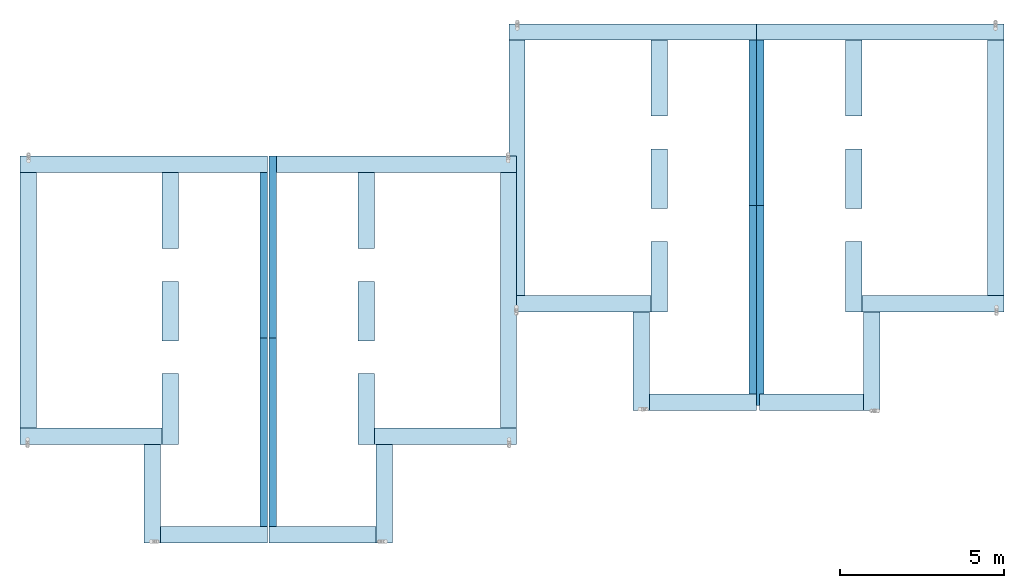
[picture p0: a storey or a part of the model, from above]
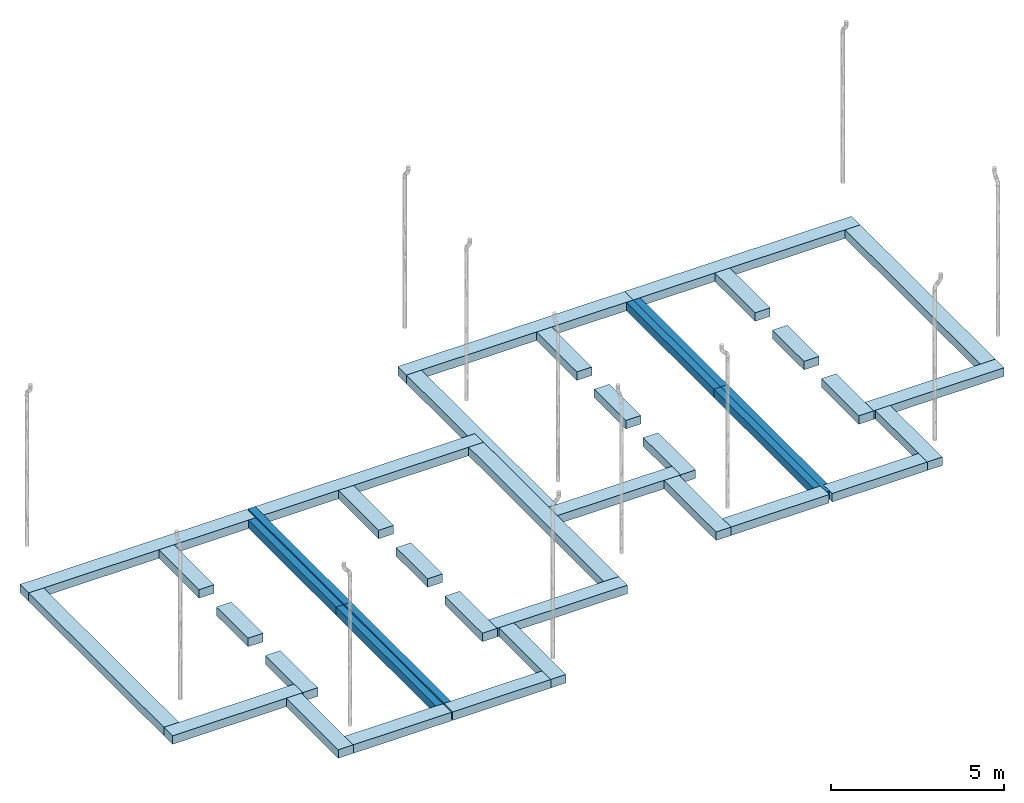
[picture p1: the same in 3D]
Properties of the parts of a building model (IFC2X3), part 1 of 2

# File
Description: ViewDefinition [CoordinationView_V2.0]
Time: 2021-05-27T10:20:56
Written by: The EXPRESS Data Manager Version 5.02.0100.07 : 28 Aug 2013
Made in: 20190327_2315(x64) - Exporter 20.0.0.377 - Interface utilisateur alternative 20.0.0.377
Comment: STEP Physical File produced by: The EXPRESS Data Manager Version 5.02.0100.07 : 28 Aug 2013 * Module: EDMstepFileFactory/EDMstandAlone * Creation date: Thu May 27 10:20:56 2021 * Host: Khodri-Mohamed * Database: C:\Users\KHODRI~1\AppData\Local\Temp\9614beee-13d8-4be9-81f7-61f1e1916cf6\63d63f3d-58b9-44f3-bbe0-b76c567fc50d\ifc * Database version: 5507 * Database creation date: Thu May 27 10:20:17 2021 * Schema: IFC2X3 * Model: DataRepository.ifc * Model creation date: Thu May 27 10:20:17 2021 * Header model: DataRepository.ifc_HeaderModel * Header model creation date: Thu May 27 10:20:17 2021 * EDMuser: sdai-user * EDMgroup: sdai-group * License ID and type: 5605 : Permanent license. Expiry date: * EDMstepFileFactory options: 020000

# IfcSite, Surface:1258945
RefLatitude: 48, 52, 53, 759999; RefLongitude: 2, 25, 58, 79999; RefElevation: 0 m

# IfcSite: Boîte aux lettres encastrée:350mm x 500mm beige (4)
Material: Peinture - Noir brillant, Peinture - Gris
Name (Boîte aux lettres encastrée:350mm x 500mm beige:...) | Group
1302522 | Groupe de modèles:muret technique:1301639
1304962 | Groupe de modèles:muret technique:1304961
1305109 | Groupe de modèles:muret technique:1305108
1305402 | Groupe de modèles:muret technique:1305401

# IfcSite: Boîtier de raccordement électrique sur base:35 x 93 x 19.7 cm (4)
Material: Polyester - Beige
Name (Boîtier de raccordement électrique sur base:35 x 93 x 19.7 cm:...) | Group
1304810 | Groupe de modèles:muret technique:1301639
1304963 | Groupe de modèles:muret technique:1304961
1305110 | Groupe de modèles:muret technique:1305108
1305403 | Groupe de modèles:muret technique:1305401

# IfcBuilding
Pset_BuildingCommon - NumberOfStoreys: 8

# IfcBuildingStorey: Niveau:Ligne du Niveau (6)
Name | LongName | Elevation (m)
Plan de fondation | Plan de fondation | -1
vs | vs | -0.8
TN | TN | -0.05
Plan des fondations Maisons 1 et 2 | Plan des fondations Maisons 1 et 2 | 0
ETAGE | ETAGE | 2.82
Egout | Egout | 5.64

# IfcSpace (12)
InteriorOrExteriorSpace: INTERNAL
Name | In | LongName | Reference
470 | Plan des fondations Maisons 1 et 2 | SALON - CUISINE | SALON - CUISINE 470
471 | Plan des fondations Maisons 1 et 2 | WC | WC 471
472 | Plan des fondations Maisons 1 et 2 | GARAGE | GARAGE 472
473 | ETAGE | Ch 2 | Ch 2 473
474 | ETAGE | Ch 1 | Ch 1 474
475 | ETAGE | SDB | SDB 475
476 | ETAGE | WC | WC 476
477 | ETAGE | Suite parentale | Suite parentale 477
478 | ETAGE | Dégt | Dégt 478
479 | ETAGE | PL | PL 479
480 | ETAGE | PL | PL 480
482 | Plan des fondations Maisons 1 et 2 | PL | PL 482

# IfcBeam: 20 x 35 ht (2)
In: Egout
Type - PredefinedType: BEAM
Type - Pset_BeamCommon - IsExternal: no; Reference: 20 x 35 ht
Type - Pset_QuantityTakeOff - Reference: 20 x 35 ht
Type - Pset_ReinforcementBarPitchOfBeam - Reference: 20 x 35 ht
Material: Béton - Béton coulé sur place
Pset_BeamCommon - Slope: 0 deg; Span: 3.39 m
Pset_QuantityTakeOff - sets with these values: 2
Name (Poutre rectangulaire - Béton:20 x 35 ht:...)
1344690 | Group: Groupe de modèles:Pavillon type:1258082
1344694

# IfcBuildingElementProxy: 1372 mm (4)
Type - Material: Métal - Chrome, Métal - Acier, Poli, Métal - Finition peinture - Ivoire, Mat, Peinture - Ivoire, Plastique - Noir, Bois - Mélaminé blanc, Bois - Mélaminé hêtre
Type - Pset_BuildingElementProxyCommon - Reference: 1372 mm
Type - Pset_QuantityTakeOff - Reference: 1372 mm
Pset_BuildingElementProxyCommon - sets with these values: 2
Name (Kitchenette - Moyenne:1372 mm:...) | In
1278551 | Plan des fondations Maisons 1 et 2 | Group: Groupe de modèles:Pavillon type:1258082
1278757 | Plan des fondations Maisons 1 et 2
1283199 | 470
1360808 | Plan des fondations Maisons 1 et 2

# IfcBuildingElementProxy: 600mm x 590mm x 820mm (8)
Type - Material: Peinture - Ivoire, Verre
Type - Pset_BuildingElementProxyCommon - Reference: 600mm x 590mm x 820mm
Type - Pset_QuantityTakeOff - Reference: 600mm x 590mm x 820mm
Pset_BuildingElementProxyCommon - sets with these values: 2
Name (Lave linge - Chargement frontal:600mm x 590mm x 820mm:...) | In
1273171 | ETAGE | Group: Groupe de modèles:Pavillon type:1258082
1273182 | ETAGE
1281591 | ETAGE | Group: Groupe de modèles:Pavillon type:1258082
1281603 | ETAGE
1283187 | 475
1283206 | 475
1360799 | ETAGE
1360811 | ETAGE

# IfcBuildingElementProxy: Default (2)
Type - Material: 02d93756_919f_4a49_a223_136f2280a471, 9169c1e4_3de5_4667_a5fd_f302d34c2fa0
Type - Pset_BuildingElementProxyCommon - Reference: Default
Type - Pset_QuantityTakeOff - Reference: Default
Pset_BuildingElementProxyCommon - sets with these values: 2
Name (balance:Default:...) | In
1507373 | 470
1526810 | Plan des fondations Maisons 1 et 2

# IfcBuildingElementProxy: Default (2)
Type - Material: d8050389_d14a_4a8c_a83b_811340fb757c, f8c2de25_1ac6_4196_9ef5_2aaffd044607
Type - Pset_BuildingElementProxyCommon - Reference: Default
Type - Pset_QuantityTakeOff - Reference: Default
Pset_BuildingElementProxyCommon - sets with these values: 2
Name (plaza (1):Default:...) | In
1503406 | 473
1503469 | 474

# IfcBuildingElementProxy: Default, in_between_table_sk3:Default:1508454
In: 477
Type - Pset_BuildingElementProxyCommon - Reference: Default
Type - Pset_QuantityTakeOff - Reference: Default
Pset_BuildingElementProxyCommon - sets with these values: 2

# IfcColumn: 20 X 20 (12)
In: TN
Type - PredefinedType: COLUMN
Type - Pset_ColumnCommon - IsExternal: no; Reference: 20 X 20; LoadBearing: yes
Type - Pset_QuantityTakeOff - Reference: 20 X 20
Type - Pset_ReinforcementBarPitchOfColumn - Reference: 20 X 20
Material: Béton - Béton coulé sur place
Pset_ColumnCommon - Slope: 0 deg
Pset_QuantityTakeOff - sets with these values: 2
Name (M_Béton-Carré-Poteau:20 X 20:...)
1285215
1285443 | Group: Groupe de modèles:Pavillon type:1258082
1285460
1333031
1333209 | Group: Groupe de modèles:Pavillon type:1258082
1333213
1342184
1343042 | Group: Groupe de modèles:Pavillon type:1258082
1343055
1360830
1360924
1360941

# IfcCovering: Plafond composé:Plafond avec isolation (10)
In: ETAGE
Type - PredefinedType: CEILING
Type - Pset_CoveringCommon - Reference: Plafond avec isolation; TotalThickness: 0.32 m
Type - Pset_QuantityTakeOff - Reference: Plafond avec isolation
Material: Isolant 0.3 m, Faux-Plafond par Défaut 0.02 m
Name (Plafond composé:Plafond avec isolation:...)
1265254
1287873
1353384
1353394
1353450
1353458
1353466
1353513
1356266
1356773

# IfcDistributionPort (4)
Description: Flow; FlowDirection: SINK
Name
Port_1516675
Port_1520012
Port_1520153
Port_1520214

# IfcDoor: 0.60m x 2.04m 3, Coulissante - Encastrée:0.60m x 2.04m 3:1283190
In: ETAGE
Type - ParameterTakesPrecedence: no; Sizeable: no; Material: Porte - Poignée, Porte - Panneau, Porte - Cadre
OverallHeight: 2.065 m; OverallWidth: 1.24 m
Pset_DoorCommon - IsExternal: no; Reference: 0.60m x 2.04m 3
Pset_QuantityTakeOff - Reference: 0.60m x 2.04m 3

# IfcDoor: 0.70m x 2.04m 2 (3)
In: ETAGE
Type - ParameterTakesPrecedence: no; Sizeable: no; Material: Porte - Poignée, Porte - Panneau, Porte - Cadre
OverallHeight: 2.065 m; OverallWidth: 1.44 m
Pset_DoorCommon - IsExternal: no; Reference: 0.70m x 2.04m 2
Pset_QuantityTakeOff - Reference: 0.70m x 2.04m 2
Name (Coulissante - Encastrée:0.70m x 2.04m 2:...)
1277792 | Group: Groupe de modèles:Pavillon type:1258082
1277804
1360802

# IfcDoor: 2.00 larg x 2.15 ht, Doors_Swing_BOUVET_Thermience_Porte-Fenetre_2V:2.00 larg x 2.15 ht:1451568
In: Plan des fondations Maisons 1 et 2
Type - OperationType: DOUBLE_DOOR_SINGLE_SWING; ParameterTakesPrecedence: no; Sizeable: no; Classification: B2030100 Glazed Doors & Entrances (Uniformat); Material: Plastique - Bouvet - Blanc W012, Metal - Bouvet - Gris, Verre - Bouvet - Vitrage, Polyamide - Bouvet - Joint-Intercalaire
Type - Doors_Swing_BOUVET_Thermience_Porte-Fenetre_2V:2.00 larg x 2.15 ht:1451568 - PanelOperation: SWINGING
OverallHeight: 2.39 m; OverallWidth: 1.98 m
Pset_DoorCommon - IsExternal: yes; Reference: 2.00 larg x 2.15 ht
Pset_ManufacturerTypeInformation - Manufacturer: BOUVET
Pset_QuantityTakeOff - Reference: 2.00 larg x 2.15 ht

# IfcDoor: 2.00 larg x 2.15 ht (2)
In: Plan des fondations Maisons 1 et 2
Type - OperationType: DOUBLE_DOOR_SINGLE_SWING; ParameterTakesPrecedence: no; Sizeable: no; Classification: B2030100 Glazed Doors & Entrances (Uniformat); Material: Plastique - Bouvet - Blanc W012, Metal - Bouvet - Gris, Verre - Bouvet - Vitrage, Polyamide - Bouvet - Joint-Intercalaire
Type - Doors_Swing_BOUVET_Thermience_Porte-Fenetre_2V:2.00 larg x 2.15 ht:1469256 - PanelOperation: SWINGING
OverallHeight: 2.39 m; OverallWidth: 1.98 m
Pset_DoorCommon - IsExternal: yes; Reference: 2.00 larg x 2.15 ht
Pset_ManufacturerTypeInformation - Manufacturer: BOUVET
Pset_QuantityTakeOff - Reference: 2.00 larg x 2.15 ht
Name (Doors_Swing_BOUVET_Thermience_Porte-Fenetre_2V:2.00 larg x 2.15 ht:...)
1469256
1527300

# IfcDoor: 2.00 larg x 2.15 ht, Doors_Swing_BOUVET_Thermience_Porte-Fenetre_2V:2.00 larg x 2.15 ht:1527374
In: Plan des fondations Maisons 1 et 2
Type - OperationType: DOUBLE_DOOR_SINGLE_SWING; ParameterTakesPrecedence: no; Sizeable: no; Classification: B2030100 Glazed Doors & Entrances (Uniformat); Material: Plastique - Bouvet - Blanc W012, Metal - Bouvet - Gris, Verre - Bouvet - Vitrage, Polyamide - Bouvet - Joint-Intercalaire
Type - Doors_Swing_BOUVET_Thermience_Porte-Fenetre_2V:2.00 larg x 2.15 ht:1527374 - PanelOperation: SWINGING
OverallHeight: 2.39 m; OverallWidth: 1.98 m; Group: Groupe de modèles:Pavillon type:1258082
Pset_DoorCommon - IsExternal: yes; Reference: 2.00 larg x 2.15 ht
Pset_ManufacturerTypeInformation - Manufacturer: BOUVET
Pset_QuantityTakeOff - Reference: 2.00 larg x 2.15 ht

# IfcDoor: 73 x 204 - (70) (7)
Type - OperationType: SINGLE_SWING_LEFT; ParameterTakesPrecedence: no; Sizeable: no; Material: Poignée Porte, Dormants Portes, Panneaux Portes
Type - FR_Simple (R):73 x 204 - (70):1257987 - PanelOperation: SWINGING
OverallHeight: 2.075 m; OverallWidth: 0.8 m
Pset_DoorCommon - IsExternal: no; Reference: 73 x 204 - (70)
Pset_QuantityTakeOff - Reference: 73 x 204 - (70)
Name (FR_Simple (R):73 x 204 - (70):...) | In | Group
1257987 | Plan des fondations Maisons 1 et 2 | Groupe de modèles:Pavillon type:1258082
1258042 | ETAGE | Groupe de modèles:Pavillon type:1258082
1258044 | ETAGE | Groupe de modèles:Pavillon type:1258082
1258045 | ETAGE | Groupe de modèles:Pavillon type:1258082
1258270 | ETAGE
1258273 | ETAGE
1283086 | Plan des fondations Maisons 1 et 2

# IfcDoor: 73 x 204 - (70) (7)
Type - OperationType: SINGLE_SWING_RIGHT; ParameterTakesPrecedence: no; Sizeable: no; Material: Poignée Porte, Dormants Portes, Panneaux Portes
Type - FR_Simple (R):73 x 204 - (70):1258043 - PanelOperation: SWINGING
OverallHeight: 2.075 m; OverallWidth: 0.8 m
Pset_DoorCommon - IsExternal: no; Reference: 73 x 204 - (70)
Pset_QuantityTakeOff - Reference: 73 x 204 - (70)
Name (FR_Simple (R):73 x 204 - (70):...) | In
1258043 | ETAGE | Group: Groupe de modèles:Pavillon type:1258082
1258046 | ETAGE | Group: Groupe de modèles:Pavillon type:1258082
1258220 | Plan des fondations Maisons 1 et 2
1258269 | ETAGE
1258271 | ETAGE
1258272 | ETAGE
1360710 | Plan des fondations Maisons 1 et 2

# IfcDoor: 83 x 204 - (80) (2)
In: Plan des fondations Maisons 1 et 2
Type - OperationType: SINGLE_SWING_LEFT; ParameterTakesPrecedence: no; Sizeable: no; Material: Poignée Porte, Dormants Portes, Panneaux Portes
Type - FR_Simple (R):83 x 204 - (80):1258140 - PanelOperation: SWINGING
OverallHeight: 2.075 m; OverallWidth: 0.9 m
Pset_DoorCommon - IsExternal: no; Reference: 83 x 204 - (80)
Pset_QuantityTakeOff - Reference: 83 x 204 - (80)
Name (FR_Simple (R):83 x 204 - (80):...)
1258140
1360637

# IfcDoor: 83 x 204 - (80) (2)
In: Plan des fondations Maisons 1 et 2
Type - OperationType: SINGLE_SWING_RIGHT; ParameterTakesPrecedence: no; Sizeable: no; Material: Poignée Porte, Dormants Portes, Panneaux Portes
Type - FR_Simple (R):83 x 204 - (80):1257906 - PanelOperation: SWINGING
OverallHeight: 2.075 m; OverallWidth: 0.9 m
Pset_DoorCommon - IsExternal: no; Reference: 83 x 204 - (80)
Pset_QuantityTakeOff - Reference: 83 x 204 - (80)
Name (FR_Simple (R):83 x 204 - (80):...)
1257906 | Group: Groupe de modèles:Pavillon type:1258082
1283006

# IfcDoor: Clearance 73 cm (10)
In: ETAGE
Type - ParameterTakesPrecedence: no; Sizeable: no; Material: Pioppo, Acciaio, Finitura pittura, Avorio, Lucido
OverallHeight: 2.18 m; OverallWidth: 0.89 m
Pset_DoorCommon - IsExternal: no; Reference: Clearance 73 cm
Pset_ManufacturerTypeInformation - Manufacturer: ECLISSE
Pset_QuantityTakeOff - Reference: Clearance 73 cm
Name (Porte battante Eclisse_Shodo:Clearance 73 cm:...)
1283125
1283126
1283127
1283128
1283129
1360745
1360746
1360747
1360748
1360749

# IfcDoor: Landscaping-Gates- La Toulousaine-La_Toulousaine-Porte_de_garage_HARMONIE_ESQUIF 2.00 larg x 2.40 ht (4)
In: Plan des fondations Maisons 1 et 2
Type - ParameterTakesPrecedence: no; Sizeable: no; Material: La-Toulousaine-Porte-de-garage-HARMONIE-ESQUIF-7, La-Toulousaine-Porte-de-garage-HARMONIE-ESQUIF-3, La-Toulousaine-Porte-de-garage-HARMONIE-ESQUIF-2, La-Toulousaine-Porte-de-garage-HARMONIE-ESQUIF-4, La-Toulousaine-Porte-de-garage-HARMONIE-ESQUIF-6, La-Toulousaine-Porte-de-garage-HARMONIE-ESQUIF-5
OverallHeight: 2 m; OverallWidth: 2.4 m
Pset_DoorCommon - IsExternal: no; Reference: Landscaping-Gates- La Toulousaine-La_Toulousaine-Porte_de_garage_HARMONIE_ESQUIF 2.00 larg x 2.40 ht
Pset_ManufacturerTypeInformation - Manufacturer: La Toulousaine
Pset_QuantityTakeOff - Reference: Landscaping-Gates- La Toulousaine-La_Toulousaine-Porte_de_garage_HARMONIE_ESQUIF 2.00 larg x 2.40 ht
Name (Landscaping-Gates- La Toulousaine-La_Toulousaine-Porte_de_garage_HARMONIE_ESQUIF:Landscaping-Gates- La Toulousaine-La_Toulousaine-Porte_de_garage_HARMONIE_ESQUIF 2.00 larg x 2.40 ht:...)
1257905 | Group: Groupe de modèles:Pavillon type:1258082
1258139
1283005
1360636

# IfcDoor: Placard coulissante - 2 panneaux (8)
In: ETAGE
Type - ParameterTakesPrecedence: no; Sizeable: no; Material: Placard - Profil, Placard - Encadrement, Placard - Porte
OverallHeight: 2.1 m; OverallWidth: 1.2 m
Pset_DoorCommon - IsExternal: no; Reference: Placard coulissante - 2 panneaux
Pset_QuantityTakeOff - Reference: Placard coulissante - 2 panneaux
Name (Placard coulissante - 2 panneaux:Placard coulissante - 2 panneaux:...)
1258057 | Group: Groupe de modèles:Pavillon type:1258082
1258058 | Group: Groupe de modèles:Pavillon type:1258082
1258284
1258285
1283138
1283139
1360757
1360758

# IfcDoor: porte entree_BelM_Marsa_FR (4)
In: Plan des fondations Maisons 1 et 2
Type - ParameterTakesPrecedence: no; Sizeable: no; Material: BELM Gris Argent, BELM Satiné Blanc 9016, BELM Satiné Gris 7039, Glass, Frosted, Matelux, Aluminum, Thermal Break, Rubber, Black, ALUMINIUM
OverallHeight: 2.2125 m; OverallWidth: 1.125 m
Pset_DoorCommon - IsExternal: yes; Reference: porte entree_BelM_Marsa_FR
Pset_ManufacturerTypeInformation - Manufacturer: Bel'M
Pset_QuantityTakeOff - Reference: porte entree_BelM_Marsa_FR
Name (porte entree_BelM_Marsa_FR:porte entree_BelM_Marsa_FR:...)
1258141
1283007
1360638
1435347 | Group: Groupe de modèles:Pavillon type:1258082

# IfcFlowTerminal: Baignoire rectangulaire - Mur:Baignoire rectangulaire - Mur 70 x 170 (4)
Material: Céramique - Blanche
Pset_DistributionFlowElementCommon - Reference: Baignoire rectangulaire - Mur 70 x 170; sets with these values: 2
Name (Baignoire rectangulaire - Mur:Baignoire rectangulaire - Mur 70 x 170:...) | In
1308454 | 475
1308814 | ETAGE | Group: Groupe de modèles:Pavillon type:1258082
1308817 | ETAGE
1360898 | ETAGE

# IfcFlowTerminal: Chauffe eau:Chauffe eau (4)
In: Plan des fondations Maisons 1 et 2
Pset_DistributionFlowElementCommon - Reference: Chauffe eau; sets with these values: 2
Name (Chauffe eau:Chauffe eau:...)
1278550 | Group: Groupe de modèles:Pavillon type:1258082
1278756
1283198
1360807

# IfcFlowTerminal: FR_Lavabos:FR_Lavabos (2)
In: ETAGE
Material: Lavabos - Porcelaine Vitrifiée Blanc, Robinet - Chrome
Pset_DistributionFlowElementCommon - Reference: FR_Lavabos; sets with these values: 2
Name (FR_Lavabos:FR_Lavabos:...)
1281590 | Group: Groupe de modèles:Pavillon type:1258082
1281602

# IfcFlowTerminal: Gouttière:Gouttière 5.60 m blanc cassé 2 (12)
In: Plan de fondation
Material: Enduit blanc cassé
Pset_DistributionFlowElementCommon - Reference: Gouttière 5.60 m blanc cassé 2; sets with these values: 2
Name (Gouttière:Gouttière 5.60 m blanc cassé 2:...)
1289670
1289789
1289950
1292380 | Group: Groupe de modèles:Pavillon type:1258082
1292381 | Group: Groupe de modèles:Pavillon type:1258082
1292382 | Group: Groupe de modèles:Pavillon type:1258082
1292481
1292482
1292483
1360838
1360839
1360840

# IfcFlowTerminal: Lavabo encastrable:Lavabo encastrable (4)
Material: Métal - Chrome poli, Porcelaine - Blanche
Pset_DistributionFlowElementCommon - Reference: Lavabo encastrable; sets with these values: 2
Name (Lavabo encastrable:Lavabo encastrable:...) | In
1257989 | Plan des fondations Maisons 1 et 2 | Group: Groupe de modèles:Pavillon type:1258082
1258222 | Plan des fondations Maisons 1 et 2
1283088 | 471
1360712 | Plan des fondations Maisons 1 et 2

# IfcFlowTerminal: M_Cuvette réservoir-3D:M_Cuvette réservoir-3D (6)
Material: Porcelaine - Lin, Stratifié - Lin,Mat
Pset_DistributionFlowElementCommon - Reference: M_Cuvette réservoir-3D; sets with these values: 2
Name (M_Cuvette réservoir-3D:M_Cuvette réservoir-3D:...) | In
1257988 | Plan des fondations Maisons 1 et 2 | Group: Groupe de modèles:Pavillon type:1258082
1258052 | ETAGE | Group: Groupe de modèles:Pavillon type:1258082
1258221 | Plan des fondations Maisons 1 et 2
1258279 | ETAGE
1283087 | 471
1360711 | Plan des fondations Maisons 1 et 2

# IfcFlowTerminal: Sanitary_Compound-Units_Roca_ARMANI-BAIA-Vanity-unit-with-washbasin:R3 - Greige (2)
Material: Roca - BAIA - R3 - Greige, Roca - BAIA - VC - Greige, Roca - BAIA - 00 - Off white
Pset_DistributionFlowElementCommon - Reference: R3 - Greige; sets with these values: 2
Name (Sanitary_Compound-Units_Roca_ARMANI-BAIA-Vanity-unit-with-washbasin:R3 - Greige:...) | In
1516675 | 475
1520214 | ETAGE

# IfcFlowTerminal: Sanitary_Toilets_Azzurra-Ceramica_Charme-wall-floor-trap-close-coupled-bac:Default (2)
Material: Ceramics-Azzurra-White
Pset_DistributionFlowElementCommon - Reference: Default; sets with these values: 2
Name (Sanitary_Toilets_Azzurra-Ceramica_Charme-wall-floor-trap-close-coupled-bac:Default:...) | In
1520012 | 476
1520153 | ETAGE

# IfcFooting: Semelle filante:semelle excentrée ht 30 cm larg 40 cm (8)
In: Plan de fondation
PredefinedType: STRIP_FOOTING; Material: Béton
Pset_QuantityTakeOff - Reference: semelle excentrée ht 30 cm larg 40 cm; sets with these values: 3
Name (Semelle filante:semelle excentrée ht 30 cm larg 40 cm:...)
1332323
1332336
1332529 | Group: Groupe de modèles:Pavillon type:1258082
1332531 | Group: Groupe de modèles:Pavillon type:1258082
1332549
1332551
1360920
1360922

# IfcFooting: Semelle filante:semelle ht 30 cm larg 50 cm (24)
In: Plan de fondation
PredefinedType: STRIP_FOOTING; Material: Béton
Pset_QuantityTakeOff - Reference: semelle ht 30 cm larg 50 cm; sets with these values: 3
Name (Semelle filante:semelle ht 30 cm larg 50 cm:...)
1332244
1332257
1332279
1332292
1332301
1332310
1332515 | Group: Groupe de modèles:Pavillon type:1258082
1332517 | Group: Groupe de modèles:Pavillon type:1258082
1332521 | Group: Groupe de modèles:Pavillon type:1258082
1332523 | Group: Groupe de modèles:Pavillon type:1258082
1332525 | Group: Groupe de modèles:Pavillon type:1258082
1332527 | Group: Groupe de modèles:Pavillon type:1258082
1332535
1332537
1332541
1332543
1332545
1332547
1360908
1360910
1360912
1360914
1360916
1360918

# IfcFurnishingElement: 1000 mm x 2000 mm 3 (6)
In: ETAGE
Type - Material: Textile - Bleu pâle, Bois - Teck, Plastique - Noir
Pset_QuantityTakeOff - Reference: 1000 mm x 2000 mm 3
Name (Lit à lattes:1000 mm x 2000 mm 3:...)
1273169 | Group: Groupe de modèles:Pavillon type:1258082
1273180
1277797 | Group: Groupe de modèles:Pavillon type:1258082
1277809
1360798
1360803

# IfcFurnishingElement: 1100 mm x 1100 mm x 760 mm (4)
Type - Material: Bois - Exotique
Pset_QuantityTakeOff - Reference: 1100 mm x 1100 mm x 760 mm
Name (MS-Table et chaises:1100 mm x 1100 mm x 760 mm:...) | In
1278547 | Plan des fondations Maisons 1 et 2 | Group: Groupe de modèles:Pavillon type:1258082
1278753 | Plan des fondations Maisons 1 et 2
1360805 | Plan des fondations Maisons 1 et 2
1526843 | 470

# IfcFurnishingElement: 1525 mm x 600 mm (3)
In: ETAGE
Type - Material: Bois - Mélaminé ivoire, Métal - Chrome, Bois - Cerisier
Pset_QuantityTakeOff - Reference: 1525 mm x 600 mm
Name (Bureau commun:1525 mm x 600 mm:...)
1273168 | Group: Groupe de modèles:Pavillon type:1258082
1273179
1360797

# IfcFurnishingElement: 1525 mm x 762 mm (3)
In: ETAGE
Type - Material: Bois - Mélaminé ivoire, Métal - Chrome, Bois - Cerisier
Pset_QuantityTakeOff - Reference: 1525 mm x 762 mm
Name (Bureau commun:1525 mm x 762 mm:...)
1273166 | Group: Groupe de modèles:Pavillon type:1258082
1273177
1360796

# IfcFurnishingElement: 1900 mm x 2000 mm (4)
Type - Material: Textile - Bleu pâle, Bois - Teck, Plastique - Noir
Pset_QuantityTakeOff - Reference: 1900 mm x 2000 mm
Name (Lit à lattes:1900 mm x 2000 mm:...) | In
1273162 | ETAGE | Group: Groupe de modèles:Pavillon type:1258082
1273173 | ETAGE
1503337 | 477
1503514 | ETAGE

# IfcFurnishingElement: 3 emplacements (230 x 92 cm) (2)
In: Plan des fondations Maisons 1 et 2
Type - Material: Métal - Chrome, Cuir - Bordeaux
Pset_QuantityTakeOff - Reference: 3 emplacements (230 x 92 cm)
Name (Banquette - 3 places:3 emplacements (230 x 92 cm):...)
1278549 | Group: Groupe de modèles:Pavillon type:1258082
1278755

# IfcFurnishingElement: Allegro 7096 (6)
In: ETAGE
Type - Material: Birch_horr, Glass
Pset_ManufacturerTypeInformation - Manufacturer: Stolab
Pset_QuantityTakeOff - Reference: Allegro 7096
Name (Allegro 7096:Allegro 7096:...)
1506108
1514179
1514273
1514572
1514752
1514753

# IfcFurnishingElement: Arm Back Rest Height - (35cm) Seat Depth - (80cm) (2)
Pset_QuantityTakeOff - Reference: Arm Back Rest Height - (35cm) Seat Depth - (80cm)
Name (Furniture_Armchairs_Mymito-GmbH_Cubit-Modular-Sofa-Armchair-Seat-Height-41-cm-Seat-Width-100-cm:Arm Back Rest Height - (35cm) Seat Depth - (80cm):...) | In
1513229 | 470
1526813 | Plan des fondations Maisons 1 et 2

# IfcFurnishingElement: Body material-(Furniture-LM-004) Metallic detail material-(Metal-LF-018)Feet material-(Metal-LF-018) (4)
Type - Material: Animovel-Furniture-LM-004, Animovel-Plastic-Black, Animovel-Glass-Clear Glass, Animovel-Metal-LF-018
Type - Pset_FurnitureTypeCommon - Description: 1 wood door, 1 glass door, 6 glass shelves, foot and motifs with lacquered metal
Pset_ManufacturerTypeInformation - Manufacturer: Animovel
Pset_QuantityTakeOff - Reference: Body material-(Furniture-LM-004) Metallic detail material-(Metal-LF-018)Feet material-(Metal-LF-018)
Name (Furniture_Shelving-Storage_Animovel_Iris-Showcase:Body material-(Furniture-LM-004) Metallic detail material-(Metal-LF-018)Feet material-(Metal-LF-018):...) | In
1511023 | 470
1513855 | 470
1526812 | ETAGE
1526814 | ETAGE

# IfcFurnishingElement: Koja_S51H (2)
Type - Material: Fabric-BLA-Koja, Koja, Upholstery-BLA-Koja-Matte, Ash_BLA-Koja
Pset_QuantityTakeOff - Reference: Koja_S51H
Name (Blå Station-Koja:Koja_S51H:...) | In
1523795 | 470
1526815 | Plan des fondations Maisons 1 et 2

# IfcFurnishingElement: Modernform 5-M-EXEC-SD-EXM4DSRF33-xxx-xx (2)
Type - Material: Black, ALUMINIUM, Classic Euroline - Vertical Line, Bright Delphes
Pset_ManufacturerTypeInformation - Manufacturer: Modernform
Pset_QuantityTakeOff - Reference: Modernform 5-M-EXEC-SD-EXM4DSRF33-xxx-xx
Name (Modernform 5-M-EXEC-SD-EXM4DSRF33-xxx-xx:Modernform 5-M-EXEC-SD-EXM4DSRF33-xxx-xx:...) | In
1283185 | 474
1504843 | 473

# IfcFurnishingElement: Table basse - Verre (2)
In: Plan des fondations Maisons 1 et 2
Type - Material: Verre - Givré, Métal - Alu brossé
Pset_QuantityTakeOff - Reference: Table basse - Verre
Name (Table basse - Verre:Table basse - Verre:...)
1278546 | Group: Groupe de modèles:Pavillon type:1258082
1278752

# IfcOpeningElement: Opening (103)
Name | In
 | ETAGE | Pset_OpeningElementCommon - Reference: Dalle Béton - 20 cm + FAUX PLAFOND; sets with these values: 2; Group: Groupe de modèles:Pavillon type:1258082
Mur de base:Ext. Parpaing 20 + Isolant 10 enduit gris:1158267 | ETAGE | Group: Groupe de modèles:Pavillon type:1258082; Pset_QuantityTakeOff - Reference: Ext. Parpaing 20 + Isolant 10 enduit gris; sets with these values: 2
3 x  | ETAGE | Pset_OpeningElementCommon - Reference: Dalle Béton - 20 cm + FAUX PLAFOND; sets with these values: 2
2 x Mur de base:Ext. Parpaing 20 + Isolant 10 enduit gris:1158267 | ETAGE | Pset_QuantityTakeOff - Reference: Ext. Parpaing 20 + Isolant 10 enduit gris; sets with these values: 2
2 x Mur de base:MITOYEN. Parpaing 10 + Isolant 10+ PLACO 2:1366783 | ETAGE | Pset_QuantityTakeOff - Reference: MITOYEN. Parpaing 10 + Isolant 10+ PLACO 2; sets with these values: 2
Mur de base:Int. Platre 70 mm en blanc:1283118 | ETAGE | Pset_QuantityTakeOff - Reference: Int. Platre 70 mm en blanc; sets with these values: 2
Mur de base:Int. Platre 70 mm en blanc:1283119 | ETAGE | Pset_QuantityTakeOff - Reference: Int. Platre 70 mm en blanc; sets with these values: 2
6 x Mur de base:modénateurs ep 2 cm gris:804914 | Plan des fondations Maisons 1 et 2 | Pset_QuantityTakeOff - Reference: modénateurs ep 2 cm gris; sets with these values: 2
2 x Mur de base:modénateurs ep 2 cm gris:804914 | Plan des fondations Maisons 1 et 2 | Group: Groupe de modèles:Pavillon type:1258082; Pset_QuantityTakeOff - Reference: modénateurs ep 2 cm gris; sets with these values: 2
Mur de base:Ext. Parpaing 20:1330094 | vs | Pset_QuantityTakeOff - Reference: Ext. Parpaing 20; sets with these values: 2
Mur de base:Ext. Parpaing 20:1332173 | vs | Group: Groupe de modèles:Pavillon type:1258082; Pset_QuantityTakeOff - Reference: Ext. Parpaing 20; sets with these values: 2
Mur de base:Ext. Parpaing 20:1332186 | vs | Pset_QuantityTakeOff - Reference: Ext. Parpaing 20; sets with these values: 2
Mur de base:Ext. Parpaing 20:1360907 | vs | Pset_QuantityTakeOff - Reference: Ext. Parpaing 20; sets with these values: 2
 | Plan des fondations Maisons 1 et 2 | Pset_OpeningElementCommon - Reference: Dalle Béton - 20 cm; sets with these values: 2
3 x Mur de base:peinture biorox 2:1359195 | ETAGE | Pset_QuantityTakeOff - Reference: peinture biorox 2; sets with these values: 2
2 x Mur de base:Ext. Parpaing 20 + Isolant 10 enduit blanc cassé:1257898 | Plan des fondations Maisons 1 et 2
2 x Mur de base:Ext. Parpaing 20 + Isolant 10 enduit blanc cassé:1257900 | Plan des fondations Maisons 1 et 2
Landscaping-Gates- La Toulousaine-La_Toulousaine-Porte_de_garage_HARMONIE_ESQUIF:Landscaping-Gates- La Toulousaine-La_Toulousaine-Porte_de_garage_HARMONIE_ESQUIF 2.00 larg x 2.40 ht:1257905:1 | Plan des fondations Maisons 1 et 2
FR_Simple (R):83 x 204 - (80):1257906:1 | Plan des fondations Maisons 1 et 2
FR_Simple (R):73 x 204 - (70):1257987:1 | Plan des fondations Maisons 1 et 2
2 x Mur de base:Ext. Parpaing 20 + Isolant 10 enduit blanc cassé:1258029 | ETAGE
Mur de base:Ext. Parpaing 20 + Isolant 10 enduit blanc cassé:1258031 | ETAGE
Mur de base:Ext. Parpaing 20 + Isolant 10 enduit gris:1258033 | ETAGE
FR_Simple (R):73 x 204 - (70):1258044:1 | ETAGE
FR_Simple (R):73 x 204 - (70):1258045:1 | ETAGE
FR_Simple (R):73 x 204 - (70):1258043:1 | ETAGE
Placard coulissante - 2 panneaux:Placard coulissante - 2 panneaux:1258058:1 | ETAGE
FR_Simple (R):73 x 204 - (70):1258046:1 | ETAGE
FR_Simple (R):73 x 204 - (70):1258042:1 | ETAGE
Placard coulissante - 2 panneaux:Placard coulissante - 2 panneaux:1258057:1 | ETAGE
2 x Mur de base:Ext. Parpaing 20 + Isolant 10 enduit blanc cassé:1258132 | Plan des fondations Maisons 1 et 2
2 x Mur de base:Ext. Parpaing 20 + Isolant 10 enduit blanc cassé:1258134 | Plan des fondations Maisons 1 et 2
Landscaping-Gates- La Toulousaine-La_Toulousaine-Porte_de_garage_HARMONIE_ESQUIF:Landscaping-Gates- La Toulousaine-La_Toulousaine-Porte_de_garage_HARMONIE_ESQUIF 2.00 larg x 2.40 ht:1258139:1 | Plan des fondations Maisons 1 et 2
FR_Simple (R):83 x 204 - (80):1258140:1 | Plan des fondations Maisons 1 et 2
FR_Simple (R):73 x 204 - (70):1258220:1 | Plan des fondations Maisons 1 et 2
2 x Mur de base:Ext. Parpaing 20 + Isolant 10 enduit blanc cassé:1258256 | ETAGE
Mur de base:Ext. Parpaing 20 + Isolant 10 enduit blanc cassé:1258258 | ETAGE
Mur de base:Ext. Parpaing 20 + Isolant 10 enduit gris:1258260 | ETAGE
FR_Simple (R):73 x 204 - (70):1258271:1 | ETAGE
FR_Simple (R):73 x 204 - (70):1258272:1 | ETAGE
FR_Simple (R):73 x 204 - (70):1258270:1 | ETAGE
Placard coulissante - 2 panneaux:Placard coulissante - 2 panneaux:1258285:1 | ETAGE
FR_Simple (R):73 x 204 - (70):1258273:1 | ETAGE
FR_Simple (R):73 x 204 - (70):1258269:1 | ETAGE
Placard coulissante - 2 panneaux:Placard coulissante - 2 panneaux:1258284:1 | ETAGE
Mur de base:Int. Platre 70 mm en blanc:1277791 | ETAGE
Mur de base:Int. Platre 70 mm en blanc:1277803 | ETAGE
2 x Mur de base:Ext. Parpaing 20 + Isolant 10 enduit blanc cassé:1282998 | Plan des fondations Maisons 1 et 2
2 x Mur de base:Ext. Parpaing 20 + Isolant 10 enduit blanc cassé:1283000 | Plan des fondations Maisons 1 et 2
Landscaping-Gates- La Toulousaine-La_Toulousaine-Porte_de_garage_HARMONIE_ESQUIF:Landscaping-Gates- La Toulousaine-La_Toulousaine-Porte_de_garage_HARMONIE_ESQUIF 2.00 larg x 2.40 ht:1283005:1 | Plan des fondations Maisons 1 et 2
FR_Simple (R):83 x 204 - (80):1283006:1 | Plan des fondations Maisons 1 et 2
FR_Simple (R):73 x 204 - (70):1283086:1 | Plan des fondations Maisons 1 et 2
2 x Mur de base:Ext. Parpaing 20 + Isolant 10 enduit blanc cassé:1283112 | ETAGE
Mur de base:Ext. Parpaing 20 + Isolant 10 enduit blanc cassé:1283114 | ETAGE
Mur de base:Ext. Parpaing 20 + Isolant 10 enduit gris:1283116 | ETAGE
Mur de base:Int. Platre 70 mm en blanc:1283118 | ETAGE
Mur de base:Int. Platre 70 mm en blanc:1283119 | ETAGE
Mur de base:Int. Platre 70 mm en blanc:1283121 | ETAGE
Placard coulissante - 2 panneaux:Placard coulissante - 2 panneaux:1283139:1 | ETAGE
Mur de base:Int. Platre 70 mm en blanc:1283123 | ETAGE
Mur de base:Int. Platre 70 mm en blanc:1283124 | ETAGE
Placard coulissante - 2 panneaux:Placard coulissante - 2 panneaux:1283138:1 | ETAGE
Mur de base:Int. Platre 70 mm en blanc:1283189 | ETAGE
2 x Mur de base:Ext. Parpaing 20 + Isolant 10 enduit blanc cassé:1360629 | Plan des fondations Maisons 1 et 2
2 x Mur de base:Ext. Parpaing 20 + Isolant 10 enduit blanc cassé:1360631 | Plan des fondations Maisons 1 et 2
Landscaping-Gates- La Toulousaine-La_Toulousaine-Porte_de_garage_HARMONIE_ESQUIF:Landscaping-Gates- La Toulousaine-La_Toulousaine-Porte_de_garage_HARMONIE_ESQUIF 2.00 larg x 2.40 ht:1360636:1 | Plan des fondations Maisons 1 et 2
FR_Simple (R):83 x 204 - (80):1360637:1 | Plan des fondations Maisons 1 et 2
FR_Simple (R):73 x 204 - (70):1360710:1 | Plan des fondations Maisons 1 et 2
2 x Mur de base:Ext. Parpaing 20 + Isolant 10 enduit blanc cassé:1360732 | ETAGE
Mur de base:Ext. Parpaing 20 + Isolant 10 enduit blanc cassé:1360734 | ETAGE
Mur de base:Ext. Parpaing 20 + Isolant 10 enduit gris:1360736 | ETAGE
Mur de base:Int. Platre 70 mm en blanc:1360738 | ETAGE
Mur de base:Int. Platre 70 mm en blanc:1360739 | ETAGE
Mur de base:Int. Platre 70 mm en blanc:1360741 | ETAGE
Placard coulissante - 2 panneaux:Placard coulissante - 2 panneaux:1360758:1 | ETAGE
Mur de base:Int. Platre 70 mm en blanc:1360743 | ETAGE
Mur de base:Int. Platre 70 mm en blanc:1360744 | ETAGE
Placard coulissante - 2 panneaux:Placard coulissante - 2 panneaux:1360757:1 | ETAGE
Mur de base:Int. Platre 70 mm en blanc:1360801 | ETAGE

# IfcOpeningElement: Recess (4)
In: Plan des fondations Maisons 1 et 2
Pset_QuantityTakeOff - Reference: Ext. Parpaing 20 + 2 x 1.5; sets with these values: 2
Name (Mur de base:Ext. Parpaing 20 + 2 x 1.5:...) | Group
1300698 | Groupe de modèles:muret technique:1301639
1304946 | Groupe de modèles:muret technique:1304961
1305093 | Groupe de modèles:muret technique:1305108
1305386 | Groupe de modèles:muret technique:1305401

# IfcRailing: Garde-corps:Type Bateau 1,25 m (4)
In: ETAGE
Material: noir acier, Finition Peinture Grise
Pset_QuantityTakeOff - Reference: Type Bateau 1,25 m
Pset_RailingCommon - IsExternal: no; Reference: Type Bateau 1,25 m; Height: 1.2192 m
Name (Garde-corps:Type Bateau 1,25 m:...)
1356151
1356236 | Group: Groupe de modèles:Pavillon type:1258082
1356243
1360964

# IfcRailing: Garde-corps:Type Bateau 1,50 m (19)
In: Plan des fondations Maisons 1 et 2
Material: Bois, Finition Peinture Grise
Pset_QuantityTakeOff - Reference: Type Bateau 1,50 m
Pset_RailingCommon - IsExternal: no; Reference: Type Bateau 1,50 m; Height: 1.2192 m
Name (Garde-corps:Type Bateau 1,50 m:...)
1234129
1234277
1234325
1234450
1234554
1234602
1234641
1234711
1234797
1234925
1257930
1257934
1258164
1258168
1262855
1263026
1263073
1283030
1360661

# IfcRoof: Toit de base:Toit - 100 brun gris (6)
In: Egout
Pset_QuantityTakeOff - Reference: Toit - 100 brun gris
Pset_RoofCommon - IsExternal: yes; Reference: Toit - 100 brun gris
Name (Toit de base:Toit - 100 brun gris:...) | ProjectedArea (m2) | TotalArea (m2)
1258065 | 66.4648 | 81.1386 | Group: Groupe de modèles:Pavillon type:1258082
1258292 | 66.4648 | 81.1386
1283145 | 66.4648 | 81.1386
1360764 | 66.4648 | 81.1386
1524019 | 32.3384 | 34.4138
1524811 | 38.6016 | 41.079

# IfcSlab: 1.00 x 1.00 x .30 (8)
In: vs
Type - PredefinedType: FLOOR; Material: Béton - Béton coulé sur place
Type - Pset_QuantityTakeOff - Reference: 1.00 x 1.00 x .30
Type - Pset_ReinforcementBarPitchOfSlab - Reference: 1.00 x 1.00 x .30
Type - Pset_SlabCommon - IsExternal: no; Reference: 1.00 x 1.00 x .30
Pset_QuantityTakeOff - sets with these values: 2
Pset_SlabCommon - PitchAngle: 0 deg
Name (Base rectangulaire:1.00 x 1.00 x .30:...)
1333656
1333931 | Group: Groupe de modèles:Pavillon type:1258082
1333937
1343296
1343491 | Group: Groupe de modèles:Pavillon type:1258082
1343496
1360935
1360943

# IfcSlab: Sol:Dalle Béton - 10 cm, Sol:Dalle Béton - 10 cm:1262435
In: Plan des fondations Maisons 1 et 2
Type - PredefinedType: FLOOR; Material: Béton 0.1 m
Type - Pset_QuantityTakeOff - Reference: Dalle Béton - 10 cm
Type - Pset_ReinforcementBarPitchOfSlab - Reference: Dalle Béton - 10 cm
Type - Pset_SlabCommon - IsExternal: no; Reference: Dalle Béton - 10 cm
Pset_QuantityTakeOff - sets with these values: 2
Pset_SlabCommon - LoadBearing: no; PitchAngle: 0 deg

# IfcSlab: Sol:Dalle Béton - 20 cm (4)
In: Plan des fondations Maisons 1 et 2
Type - PredefinedType: FLOOR; Material: Béton 0.2 m
Type - Pset_QuantityTakeOff - Reference: Dalle Béton - 20 cm
Type - Pset_ReinforcementBarPitchOfSlab - Reference: Dalle Béton - 20 cm
Type - Pset_SlabCommon - IsExternal: no; Reference: Dalle Béton - 20 cm
Pset_QuantityTakeOff - sets with these values: 2
Pset_SlabCommon - LoadBearing: no; PitchAngle: 0 deg
Name (Sol:Dalle Béton - 20 cm:...)
1333265
1333589 | Group: Groupe de modèles:Pavillon type:1258082
1333599
1360928

# IfcSlab: Sol:Dalle Béton - 20 cm + FAUX PLAFOND (4)
In: ETAGE
Type - PredefinedType: FLOOR; Material: Béton 0.2 m, Isolant 0.1 m, Plastique - Blanc 0.02 m
Type - Pset_QuantityTakeOff - Reference: Dalle Béton - 20 cm + FAUX PLAFOND
Type - Pset_ReinforcementBarPitchOfSlab - Reference: Dalle Béton - 20 cm + FAUX PLAFOND
Type - Pset_SlabCommon - IsExternal: no; Reference: Dalle Béton - 20 cm + FAUX PLAFOND
Pset_QuantityTakeOff - sets with these values: 2
Pset_SlabCommon - LoadBearing: no; PitchAngle: 0 deg
Name (Sol:Dalle Béton - 20 cm + FAUX PLAFOND:...)
1257996 | Group: Groupe de modèles:Pavillon type:1258082
1258229
1283094
1360718

# IfcSlab: Sol:Dalle Béton butume rouge - 10 cm (9)
In: Plan des fondations Maisons 1 et 2
Type - PredefinedType: FLOOR; Material: Métal 0.1 m
Type - Pset_QuantityTakeOff - Reference: Dalle Béton butume rouge - 10 cm
Type - Pset_ReinforcementBarPitchOfSlab - Reference: Dalle Béton butume rouge - 10 cm
Type - Pset_SlabCommon - IsExternal: no; Reference: Dalle Béton butume rouge - 10 cm
Pset_QuantityTakeOff - sets with these values: 2
Pset_SlabCommon - LoadBearing: no; PitchAngle: 0 deg
Name (Sol:Dalle Béton butume rouge - 10 cm:...)
1259101
1259423
1259624
1259930
1260664 | Group: Groupe de modèles:Pavillon type:1258082
1260672
1283178
1305559
1360790

# IfcSlab: Sol:LAME DE BAMBOU (279)
In: ETAGE
Type - PredefinedType: FLOOR; Material: PARQUET BAMBOU 0.01 m
Type - Pset_QuantityTakeOff - Reference: LAME DE BAMBOU
Type - Pset_ReinforcementBarPitchOfSlab - Reference: LAME DE BAMBOU
Type - Pset_SlabCommon - IsExternal: no; Reference: LAME DE BAMBOU
Pset_QuantityTakeOff - sets with these values: 2
Pset_SlabCommon - LoadBearing: no; PitchAngle: 0 deg
Name (Sol:LAME DE BAMBOU:...)
1376428
1377877
1377894
1377908
1377965
1378024
1378038
1378054
1378068
1378203
1378210
1378217
1378224
1378231
1378238
1378245
1378252
1378259
1378275
1378282
1378289
1378296
1378303
1378310
1378317
1378324
1378331
1378347
1378354
1378361
1378368
1378375
1378382
1378389
1378396
1378403
1378425
1378432
1378439
1378446
1378453
1378460
1378467
1378474
1378481
1378488
1378495
1378502
1378509
1378516
1378523
1378530
1378537
1378544
1378551
1378558
1378565
1378572
1378579
1378586
1378593
1378600
1378607
1378614
1378621
1378628
1378635
1378642
1378649
1378656
1378663
1378670
1378692
1378699
1378706
1378713
1378720
1378727
1378734
1378741
1378748
1378755
1378762
1378769
1378776
1378783
1378790
1378797
1378804
1378811
1378818
1378825
1378832
1378839
1378846
1378853
1378860
1378867
1378874
1378881
1378888
1378895
1378902
1378909
1378916
1378923
1378930
1378937
1378959
1378966
1378973
1378980
1378987
1378994
1379001
1379008
1379015
1379022
1379029
1379036
1379043
1379050
1379057
1379064
1379071
1379085
1379092
1379099
1379113
1379120
1379127
1379134
1379148
1379155
1379162
1379176
1379183
1379190
1379197
1379283
1379297
1379313
1379397
1379411
1379425
1379473
1379480
1379487
1379503
1379510
1379517
1379532
1379539
1379546
1379561
1379568
1379575
1379683
1379697
1379720
1379743
1379750
1379757
1379771
1379778
1379785
1380610
1380617
1380624
1380702
1380709
1380716
1380723
1380762
1380769
1380776
1380832
1380839
1380846
1380853
1380860
1380867
1380874
1380892
1380899
1380906
1380913
1380920
1380927
1380934
1380970
1380977
1380984
1380991
1380998
1381050
1381057
1381064
1381126
1381133
1381140
1381220
1381227
1381234
1381265
1381272
1381279
1381286
1381293
1381300
1381318
1381325
1381332
1381339
1381346
1381353
1381375
1381382
1381389
1381396
1381403
1381410
1381432
1381439
1381446
1381453
1381460
1381467
1381489
1381496
1381503
1381510
1381517
1381524
1381542
1381549
1381556
1381563
1381570
1381577
1381597
1381604
1381611
1381618
1381625
1381632
1381650
1381657
1381664
1381671
1381678
1381685
1381705
1381712
1381719
1381726
1381733
1381740
1381762
1381769
1381776
1381783
1381790
1381797
1381817
1381824
1381831
1381838
1381845
1381852
1381874
1381881
1381888
1381895
1381902
1381909
1381927
1381934
1381941

# IfcSlab: Toit de base:Toit - 100 brun gris (10)
In: Egout
PredefinedType: ROOF; Material: gris 0.05 m
Pset_QuantityTakeOff - Reference: Toit - 100 brun gris; sets with these values: 2
Pset_SlabCommon - IsExternal: yes; Reference: Toit - 100 brun gris
Name (Toit de base:Toit - 100 brun gris:...) | PitchAngle (deg)
2 x 1258065 | 35 | Group: Groupe de modèles:Pavillon type:1258082
2 x 1258292 | 35
2 x 1283145 | 35
2 x 1360764 | 35
1524019 | 20
1524811 | 20

# IfcStair: Escalier coulé sur place:Monobloc (4)
In: Plan des fondations Maisons 1 et 2
Pset_QuantityTakeOff - Reference: Monobloc
Pset_StairCommon - Reference: Monobloc; IsExternal: no; NumberOfRiser: 17; NumberOfTreads: 16; RiserHeight: 0.177647 m; TreadLength: 0.274706 m
Name (Escalier coulé sur place:Escalier:...)
1257909 | Group: Groupe de modèles:Pavillon type:1258082
1258143
1283009
1360640

# IfcStair: Escalier:Monobloc (22)
In: Plan des fondations Maisons 1 et 2
Pset_QuantityTakeOff - Reference: Monobloc
Pset_StairCommon - Reference: Monobloc; IsExternal: no
Name (Escalier:Monobloc:...) | NumberOfRiser = NumberOfTreads | RiserHeight (m) | TreadLength (m)
78219 | 15 | 0.173333 | 0.283333
78348 | 15 | 0.173333 | 0.283333
277315 | 17 | 0.158824 | 0.312353
277472 | 17 | 0.158824 | 0.312353
277700 | 17 | 0.158824 | 0.312353
277873 | 17 | 0.158824 | 0.312353
342772 | 15 | 0.18 | 0.27
342952 | 15 | 0.18 | 0.27
343084 | 15 | 0.18 | 0.27
343204 | 15 | 0.18 | 0.27
352512 | 15 | 0.18 | 0.27
353029 | 15 | 0.18 | 0.27
368055 | 15 | 0.18 | 0.27
368180 | 15 | 0.18 | 0.27
368300 | 14 | 0.18 | 0.27
369629 | 15 | 0.18 | 0.27
373361 | 15 | 0.18 | 0.27
373488 | 15 | 0.18 | 0.27
376794 | 15 | 0.18 | 0.27
384406 | 15 | 0.18 | 0.27
384573 | 14 | 0.18 | 0.27
384807 | 15 | 0.18 | 0.27

# IfcStair: Escalier:Monobloc 2, Escalier:Monobloc 2:515021
In: Plan des fondations Maisons 1 et 2
Pset_QuantityTakeOff - Reference: Monobloc 2
Pset_StairCommon - IsExternal: no; Reference: Monobloc 2; NumberOfRiser: 15; NumberOfTreads: 15; RiserHeight: 0.18 m; TreadLength: 0.3 m

# IfcStairFlight: Volée monobloc:Nez de marche 5 mm (4)
In: Plan des fondations Maisons 1 et 2
NumberOfRiser: 17; NumberOfTreads: 16; RiserHeight: 0.582832 m; TreadLength: 0.901266 m
Pset_QuantityTakeOff - Reference: Nez de marche 5 mm
Pset_StairFlightCommon - Reference: Nez de marche 5 mm; NumberOfRiser: 17; NumberOfTreads: 16; RiserHeight: 0.177647 m; TreadLength: 0.274706 m; NosingLength: 0.005 m; TreadLengthAtOffset: 0.274706 m
Name (Escalier coulé sur place:Escalier:...)
1257909 Run 1 | Group: Groupe de modèles:Pavillon type:1258082
1258143 Run 1
1283009 Run 1
1360640 Run 1

# IfcWall: Mur de base:peinture biorox 1, Mur de base:peinture biorox 1:1371419
In: ETAGE
Type - PredefinedType: STANDARD; Material: biorox 1 0.002 m
Type - Pset_QuantityTakeOff - Reference: peinture biorox 1
Type - Pset_ReinforcementBarPitchOfWall - Reference: peinture biorox 1
Type - Pset_WallCommon - IsExternal: no; Reference: peinture biorox 1
Pset_QuantityTakeOff - sets with these values: 2
Pset_WallCommon - IsExternal: yes; ExtendToStructure: no; LoadBearing: no

# IfcWallStandardCase: Mur de base:Ext. Parpaing 10 (8)
In: vs
Type - PredefinedType: STANDARD; Material: Parpaing 0.1 m
Type - Pset_QuantityTakeOff - Reference: Ext. Parpaing 10
Type - Pset_ReinforcementBarPitchOfWall - Reference: Ext. Parpaing 10
Type - Pset_WallCommon - IsExternal: no; Reference: Ext. Parpaing 10
Pset_QuantityTakeOff - sets with these values: 2
Pset_WallCommon - IsExternal: yes; ExtendToStructure: no; LoadBearing: no
Name (Mur de base:Ext. Parpaing 10:...)
1330088
1330091
1332169 | Group: Groupe de modèles:Pavillon type:1258082
1332170 | Group: Groupe de modèles:Pavillon type:1258082
1332182
1332183
1360903
1360904

# IfcWallStandardCase: Mur de base:Ext. Parpaing 10 + 2 x 1.5 2 (4)
In: Plan des fondations Maisons 1 et 2
Type - PredefinedType: STANDARD; Material: Enduit blanc cassé2 0.015 m, Parpaing 0.1 m, Enduit blanc cassé2 0.015 m
Type - Pset_QuantityTakeOff - Reference: Ext. Parpaing 10 + 2 x 1.5 2
Type - Pset_ReinforcementBarPitchOfWall - Reference: Ext. Parpaing 10 + 2 x 1.5 2
Type - Pset_WallCommon - IsExternal: no; Reference: Ext. Parpaing 10 + 2 x 1.5 2
Pset_QuantityTakeOff - sets with these values: 2
Pset_WallCommon - IsExternal: yes; ExtendToStructure: no; LoadBearing: no
Name (Mur de base:Ext. Parpaing 10 + 2 x 1.5 2:...)
1257903 | Group: Groupe de modèles:Pavillon type:1258082
1258137
1283003
1360634

# IfcWallStandardCase: Mur de base:Ext. Parpaing 10 + Isolant 10 enduit blanc cassé (4)
In: Plan des fondations Maisons 1 et 2
Type - PredefinedType: STANDARD; Material: Enduit blanc cassé2 0.02 m, Parpaing 0.1 m, Isolant 0.1 m
Type - Pset_QuantityTakeOff - Reference: Ext. Parpaing 10 + Isolant 10 enduit blanc cassé
Type - Pset_ReinforcementBarPitchOfWall - Reference: Ext. Parpaing 10 + Isolant 10 enduit blanc cassé
Type - Pset_WallCommon - IsExternal: no; Reference: Ext. Parpaing 10 + Isolant 10 enduit blanc cassé
Pset_QuantityTakeOff - sets with these values: 2
Pset_WallCommon - IsExternal: yes; ExtendToStructure: no; LoadBearing: no
Name (Mur de base:Ext. Parpaing 10 + Isolant 10 enduit blanc cassé:...)
1257899 | Group: Groupe de modèles:Pavillon type:1258082
1258133
1282999
1360630

# IfcWallStandardCase: Mur de base:Ext. Parpaing 2 + 20 + 2 gris (8)
In: Plan des fondations Maisons 1 et 2
Type - PredefinedType: STANDARD; Material: Enduit gris 0.02 m, Parpaing 0.2 m, Enduit gris 0.02 m
Type - Pset_QuantityTakeOff - Reference: Ext. Parpaing 2 + 20 + 2 gris
Type - Pset_ReinforcementBarPitchOfWall - Reference: Ext. Parpaing 2 + 20 + 2 gris
Type - Pset_WallCommon - IsExternal: no; Reference: Ext. Parpaing 2 + 20 + 2 gris
Pset_QuantityTakeOff - sets with these values: 2
Pset_WallCommon - IsExternal: yes; ExtendToStructure: no; LoadBearing: no
Name (Mur de base:Ext. Parpaing 2 + 20 + 2 gris:...)
1257901 | Group: Groupe de modèles:Pavillon type:1258082
1257904 | Group: Groupe de modèles:Pavillon type:1258082
1258135
1258138
1283001
1283004
1360632
1360635

# IfcWallStandardCase: Mur de base:Ext. Parpaing 20 (24)
In: vs
Type - PredefinedType: STANDARD; Material: Parpaing 0.2 m
Type - Pset_QuantityTakeOff - Reference: Ext. Parpaing 20
Type - Pset_ReinforcementBarPitchOfWall - Reference: Ext. Parpaing 20
Type - Pset_WallCommon - IsExternal: no; Reference: Ext. Parpaing 20
Pset_QuantityTakeOff - sets with these values: 2
Pset_WallCommon - IsExternal: yes; LoadBearing: no
Name (Mur de base:Ext. Parpaing 20:...) | ExtendToStructure
1330083 | no
1330084 | yes
1330085 | yes
1330092 | yes
1330093 | yes
1330094 | yes
1332165 | no | Group: Groupe de modèles:Pavillon type:1258082
1332166 | no | Group: Groupe de modèles:Pavillon type:1258082
1332167 | no | Group: Groupe de modèles:Pavillon type:1258082
1332171 | no | Group: Groupe de modèles:Pavillon type:1258082
1332172 | no | Group: Groupe de modèles:Pavillon type:1258082
1332173 | no | Group: Groupe de modèles:Pavillon type:1258082
1332178 | no
1332179 | no
1332180 | no
1332184 | no
1332185 | no
1332186 | no
1360900 | no
1360901 | yes
1360902 | yes
1360905 | yes
1360906 | yes
1360907 | yes

# IfcWallStandardCase: Mur de base:Ext. Parpaing 20 + 2 x 1.5 (6)
Type - PredefinedType: STANDARD; Material: Enduit blanc cassé2 0.015 m, Parpaing 0.2 m, Enduit blanc cassé2 0.015 m
Type - Pset_QuantityTakeOff - Reference: Ext. Parpaing 20 + 2 x 1.5
Type - Pset_ReinforcementBarPitchOfWall - Reference: Ext. Parpaing 20 + 2 x 1.5
Type - Pset_WallCommon - IsExternal: no; Reference: Ext. Parpaing 20 + 2 x 1.5
Pset_QuantityTakeOff - sets with these values: 2
Pset_WallCommon - IsExternal: yes; ExtendToStructure: no; LoadBearing: no
Name (Mur de base:Ext. Parpaing 20 + 2 x 1.5:...) | In | Group
1300698 | Plan des fondations Maisons 1 et 2 | Groupe de modèles:muret technique:1301639
1304946 | Plan des fondations Maisons 1 et 2 | Groupe de modèles:muret technique:1304961
1305093 | Plan des fondations Maisons 1 et 2 | Groupe de modèles:muret technique:1305108
1305386 | Plan des fondations Maisons 1 et 2 | Groupe de modèles:muret technique:1305401
1349624 | ETAGE | Groupe de modèles:Pavillon type:1258082
1349628 | ETAGE

# IfcWallStandardCase: Mur de base:Ext. Parpaing 20 + Isolant 10 enduit blanc cassé (23)
Type - PredefinedType: STANDARD; Material: Enduit blanc cassé2 0.02 m, Parpaing 0.2 m, Isolant 0.1 m
Type - Pset_QuantityTakeOff - Reference: Ext. Parpaing 20 + Isolant 10 enduit blanc cassé
Type - Pset_ReinforcementBarPitchOfWall - Reference: Ext. Parpaing 20 + Isolant 10 enduit blanc cassé
Type - Pset_WallCommon - IsExternal: no; Reference: Ext. Parpaing 20 + Isolant 10 enduit blanc cassé
Pset_QuantityTakeOff - sets with these values: 2
Pset_WallCommon - IsExternal: yes; LoadBearing: no
Name (Mur de base:Ext. Parpaing 20 + Isolant 10 enduit blanc cassé:...) | In | ExtendToStructure
1257897 | Plan des fondations Maisons 1 et 2 | no | Group: Groupe de modèles:Pavillon type:1258082
1257898 | Plan des fondations Maisons 1 et 2 | no | Group: Groupe de modèles:Pavillon type:1258082
1257900 | Plan des fondations Maisons 1 et 2 | no | Group: Groupe de modèles:Pavillon type:1258082
1258029 | ETAGE | yes | Group: Groupe de modèles:Pavillon type:1258082
1258030 | ETAGE | yes | Group: Groupe de modèles:Pavillon type:1258082
1258031 | ETAGE | yes | Group: Groupe de modèles:Pavillon type:1258082
1258131 | Plan des fondations Maisons 1 et 2 | no
1258132 | Plan des fondations Maisons 1 et 2 | no
1258134 | Plan des fondations Maisons 1 et 2 | no
1258256 | ETAGE | yes
1258257 | ETAGE | yes
1258258 | ETAGE | yes
1282997 | Plan des fondations Maisons 1 et 2 | yes
1282998 | Plan des fondations Maisons 1 et 2 | no
1283000 | Plan des fondations Maisons 1 et 2 | no
1283112 | ETAGE | yes
1283114 | ETAGE | yes
1360628 | Plan des fondations Maisons 1 et 2 | no
1360629 | Plan des fondations Maisons 1 et 2 | no
1360631 | Plan des fondations Maisons 1 et 2 | no
1360732 | ETAGE | yes
1360733 | ETAGE | yes
1360734 | ETAGE | yes

# IfcWallStandardCase: Mur de base:Ext. Parpaing 20 + Isolant 10 enduit gris (8)
In: ETAGE
Type - PredefinedType: STANDARD; Material: Enduit gris 0.02 m, Parpaing 0.2 m, Isolant 0.1 m
Type - Pset_QuantityTakeOff - Reference: Ext. Parpaing 20 + Isolant 10 enduit gris
Type - Pset_ReinforcementBarPitchOfWall - Reference: Ext. Parpaing 20 + Isolant 10 enduit gris
Type - Pset_WallCommon - IsExternal: no; Reference: Ext. Parpaing 20 + Isolant 10 enduit gris
Pset_QuantityTakeOff - sets with these values: 2
Pset_WallCommon - IsExternal: yes; LoadBearing: no
Name (Mur de base:Ext. Parpaing 20 + Isolant 10 enduit gris:...) | ExtendToStructure
1258032 | no | Group: Groupe de modèles:Pavillon type:1258082
1258033 | yes | Group: Groupe de modèles:Pavillon type:1258082
1258259 | no
1258260 | yes
1283115 | no
1283116 | yes
1360735 | yes
1360736 | yes

# IfcWallStandardCase: Mur de base:Int. Platre 100 mm en blanc 2 (8)
In: Plan des fondations Maisons 1 et 2
Type - PredefinedType: STANDARD; Material: Peinture - Blanc 0.1 m
Type - Pset_QuantityTakeOff - Reference: Int. Platre 100 mm en blanc 2
Type - Pset_ReinforcementBarPitchOfWall - Reference: Int. Platre 100 mm en blanc 2
Type - Pset_WallCommon - IsExternal: no; Reference: Int. Platre 100 mm en blanc 2
Pset_QuantityTakeOff - sets with these values: 2
Pset_WallCommon - ExtendToStructure: no; LoadBearing: no
Name (Mur de base:Int. Platre 100 mm en blanc 2:...)
1257902 | Group: Groupe de modèles:Pavillon type:1258082
1258136
1282288 | Group: Groupe de modèles:Pavillon type:1258082
1282292
1283002
1283210
1360633
1360814

# IfcWallStandardCase: Mur de base:Int. Platre 70 mm en blanc (82)
Type - PredefinedType: STANDARD; Material: Peinture - Blanc 0.07 m
Type - Pset_QuantityTakeOff - Reference: Int. Platre 70 mm en blanc
Type - Pset_ReinforcementBarPitchOfWall - Reference: Int. Platre 70 mm en blanc
Type - Pset_WallCommon - IsExternal: no; Reference: Int. Platre 70 mm en blanc
Pset_QuantityTakeOff - sets with these values: 2
Pset_WallCommon - ExtendToStructure: no; LoadBearing: no
Name (Mur de base:Int. Platre 70 mm en blanc:...) | In
1257981 | Plan des fondations Maisons 1 et 2 | Group: Groupe de modèles:Pavillon type:1258082
1257982 | Plan des fondations Maisons 1 et 2 | Group: Groupe de modèles:Pavillon type:1258082
1257983 | Plan des fondations Maisons 1 et 2 | Group: Groupe de modèles:Pavillon type:1258082
1257984 | Plan des fondations Maisons 1 et 2 | Group: Groupe de modèles:Pavillon type:1258082
1257985 | Plan des fondations Maisons 1 et 2 | Group: Groupe de modèles:Pavillon type:1258082
1258035 | ETAGE | Group: Groupe de modèles:Pavillon type:1258082
1258036 | ETAGE | Group: Groupe de modèles:Pavillon type:1258082
1258037 | ETAGE | Group: Groupe de modèles:Pavillon type:1258082
1258038 | ETAGE | Group: Groupe de modèles:Pavillon type:1258082
1258039 | ETAGE | Group: Groupe de modèles:Pavillon type:1258082
1258040 | ETAGE | Group: Groupe de modèles:Pavillon type:1258082
1258041 | ETAGE | Group: Groupe de modèles:Pavillon type:1258082
1258047 | ETAGE | Group: Groupe de modèles:Pavillon type:1258082
1258048 | ETAGE | Group: Groupe de modèles:Pavillon type:1258082
1258214 | Plan des fondations Maisons 1 et 2
1258215 | Plan des fondations Maisons 1 et 2
1258216 | Plan des fondations Maisons 1 et 2
1258217 | Plan des fondations Maisons 1 et 2
1258218 | Plan des fondations Maisons 1 et 2
1258262 | ETAGE
1258263 | ETAGE
1258264 | ETAGE
1258265 | ETAGE
1258266 | ETAGE
1258267 | ETAGE
1258268 | ETAGE
1258274 | ETAGE
1258275 | ETAGE
1277790 | ETAGE | Group: Groupe de modèles:Pavillon type:1258082
1277791 | ETAGE | Group: Groupe de modèles:Pavillon type:1258082
1277802 | ETAGE
1277803 | ETAGE
1283080 | Plan des fondations Maisons 1 et 2
1283081 | Plan des fondations Maisons 1 et 2
1283082 | Plan des fondations Maisons 1 et 2
1283083 | Plan des fondations Maisons 1 et 2
1283084 | Plan des fondations Maisons 1 et 2
1283118 | ETAGE
1283119 | ETAGE
1283120 | ETAGE
1283121 | ETAGE
1283122 | ETAGE
1283123 | ETAGE
1283124 | ETAGE
1283130 | ETAGE
1283131 | ETAGE
1283188 | ETAGE
1283189 | ETAGE
1286010 | Plan des fondations Maisons 1 et 2
1286236 | Plan des fondations Maisons 1 et 2 | Group: Groupe de modèles:Pavillon type:1258082
1286241 | Plan des fondations Maisons 1 et 2
1286274 | Plan des fondations Maisons 1 et 2
1286300 | Plan des fondations Maisons 1 et 2
1286468 | Plan des fondations Maisons 1 et 2 | Group: Groupe de modèles:Pavillon type:1258082
1286469 | Plan des fondations Maisons 1 et 2 | Group: Groupe de modèles:Pavillon type:1258082
1286473 | Plan des fondations Maisons 1 et 2
1286474 | Plan des fondations Maisons 1 et 2
1308594 | ETAGE
1308815 | ETAGE | Group: Groupe de modèles:Pavillon type:1258082
1308818 | ETAGE
1360704 | Plan des fondations Maisons 1 et 2
1360705 | Plan des fondations Maisons 1 et 2
1360706 | Plan des fondations Maisons 1 et 2
1360707 | Plan des fondations Maisons 1 et 2
1360708 | Plan des fondations Maisons 1 et 2
1360738 | ETAGE
1360739 | ETAGE
1360740 | ETAGE
1360741 | ETAGE
1360742 | ETAGE
1360743 | ETAGE
1360744 | ETAGE
1360750 | ETAGE
1360751 | ETAGE
1360800 | ETAGE
1360801 | ETAGE
1360832 | Plan des fondations Maisons 1 et 2
1360833 | Plan des fondations Maisons 1 et 2
1360834 | Plan des fondations Maisons 1 et 2
1360899 | ETAGE
1516927 | ETAGE
1516965 | ETAGE

# IfcWallStandardCase: Mur de base:MITOYEN. Parpaing 10 + Isolant 10+ PLACO 2 (4)
In: ETAGE
Type - PredefinedType: STANDARD; Material: Enduit blanc cassé2 0.02 m, Parpaing 0.1 m, Isolant 0.1 m
Type - Pset_QuantityTakeOff - Reference: MITOYEN. Parpaing 10 + Isolant 10+ PLACO 2
Type - Pset_ReinforcementBarPitchOfWall - Reference: MITOYEN. Parpaing 10 + Isolant 10+ PLACO 2
Type - Pset_WallCommon - IsExternal: no; Reference: MITOYEN. Parpaing 10 + Isolant 10+ PLACO 2
Pset_QuantityTakeOff - sets with these values: 2
Pset_WallCommon - IsExternal: yes; LoadBearing: no; ExtendToStructure: yes
Name (Mur de base:MITOYEN. Parpaing 10 + Isolant 10+ PLACO 2:...)
1258034 | Group: Groupe de modèles:Pavillon type:1258082
1258261
1283117
1360737

# IfcWallStandardCase: Mur de base:Mur exterieure en pierre - Ext. 500 MM (5)
In: Plan des fondations Maisons 1 et 2
Type - PredefinedType: STANDARD; Material: Mur par défaut 0.5 m
Type - Pset_QuantityTakeOff - Reference: Mur exterieure en pierre - Ext. 500 MM
Type - Pset_ReinforcementBarPitchOfWall - Reference: Mur exterieure en pierre - Ext. 500 MM
Type - Pset_WallCommon - IsExternal: no; Reference: Mur exterieure en pierre - Ext. 500 MM
Pset_QuantityTakeOff - sets with these values: 2
Pset_WallCommon - IsExternal: yes; ExtendToStructure: no; LoadBearing: no
Name (Mur de base:Mur exterieure en pierre - Ext. 500 MM:...)
1325408
1325879
1326033
1326181
1328455

# IfcWallStandardCase: Mur de base:PAPIER PEINT Jardin Sarcelle (2)
In: ETAGE
Type - PredefinedType: STANDARD; Material: papier peint jardin sarcelle 0.002 m
Type - Pset_QuantityTakeOff - Reference: PAPIER PEINT Jardin Sarcelle
Type - Pset_ReinforcementBarPitchOfWall - Reference: PAPIER PEINT Jardin Sarcelle
Type - Pset_WallCommon - IsExternal: no; Reference: PAPIER PEINT Jardin Sarcelle
Pset_QuantityTakeOff - sets with these values: 2
Pset_WallCommon - IsExternal: yes; ExtendToStructure: no; LoadBearing: no
Name (Mur de base:PAPIER PEINT Jardin Sarcelle:...)
1375371
1382603

# IfcWallStandardCase: Mur de base:PLINTHE EN BOIS (3)
In: ETAGE
Type - PredefinedType: STANDARD; Material: Blanc - Element de salle de bains 0.002 m
Type - Pset_QuantityTakeOff - Reference: PLINTHE EN BOIS
Type - Pset_ReinforcementBarPitchOfWall - Reference: PLINTHE EN BOIS
Type - Pset_WallCommon - IsExternal: no; Reference: PLINTHE EN BOIS
Pset_QuantityTakeOff - sets with these values: 2
Pset_WallCommon - IsExternal: yes; ExtendToStructure: no; LoadBearing: no
Name (Mur de base:PLINTHE EN BOIS:...)
1363075
1377456
1380331

# IfcWallStandardCase: Mur de base:modénateurs ep 2 cm gris (8)
In: Plan des fondations Maisons 1 et 2
Type - PredefinedType: STANDARD; Material: Enduit blanc cassé 0.01 m, Parpaing 0.01 m, Enduit blanc cassé 0.01 m
Type - Pset_QuantityTakeOff - Reference: modénateurs ep 2 cm gris
Type - Pset_ReinforcementBarPitchOfWall - Reference: modénateurs ep 2 cm gris
Type - Pset_WallCommon - IsExternal: no; Reference: modénateurs ep 2 cm gris
Pset_QuantityTakeOff - sets with these values: 2
Pset_WallCommon - IsExternal: yes; ExtendToStructure: no; LoadBearing: no
Name (Mur de base:modénateurs ep 2 cm gris:...)
1290335
1291060
1292383 | Group: Groupe de modèles:Pavillon type:1258082
1292442 | Group: Groupe de modèles:Pavillon type:1258082
1292484
1292543
1360841
1360880

# IfcWallStandardCase: Mur de base:peinture biorox 1, Mur de base:peinture biorox 1:1369642
In: ETAGE
Type - PredefinedType: STANDARD; Material: biorox 1 0.002 m
Type - Pset_QuantityTakeOff - Reference: peinture biorox 1
Type - Pset_ReinforcementBarPitchOfWall - Reference: peinture biorox 1
Type - Pset_WallCommon - IsExternal: no; Reference: peinture biorox 1
Pset_QuantityTakeOff - sets with these values: 2
Pset_WallCommon - IsExternal: yes; ExtendToStructure: no; LoadBearing: no

# IfcWallStandardCase: Mur de base:peinture biorox 2 (4)
In: ETAGE
Type - PredefinedType: STANDARD; Material: biorox 2 0.002 m
Type - Pset_QuantityTakeOff - Reference: peinture biorox 2
Type - Pset_ReinforcementBarPitchOfWall - Reference: peinture biorox 2
Type - Pset_WallCommon - IsExternal: no; Reference: peinture biorox 2
Pset_QuantityTakeOff - sets with these values: 2
Pset_WallCommon - IsExternal: yes; ExtendToStructure: no; LoadBearing: no
Name (Mur de base:peinture biorox 2:...)
1362745
1364161
1369626
1371408

# IfcWindow: 1.20 x 1.35 ht (19)
Type - ParameterTakesPrecedence: no; Sizeable: no; Classification: B2020100 Windows (Uniformat); Material: Plastique - Bouvet - Blanc W012, Verre - Bouvet - Vitrage, Polyamide - Bouvet - Joint-Intercalaire
OverallHeight: 1.6 m; OverallWidth: 1.28 m
Pset_ManufacturerTypeInformation - Manufacturer: BOUVET
Pset_QuantityTakeOff - Reference: 1.20 x 1.35 ht
Pset_WindowCommon - IsExternal: yes; Reference: 1.20 x 1.35 ht
Name (Windows_Opening-Hinge_BOUVET_Thermience_Fenetre_2V:1.20 x 1.35 ht:...) | In
1257908 | Plan des fondations Maisons 1 et 2 | Group: Groupe de modèles:Pavillon type:1258082
1257991 | Plan des fondations Maisons 1 et 2 | Group: Groupe de modèles:Pavillon type:1258082
1258054 | ETAGE | Group: Groupe de modèles:Pavillon type:1258082
1258055 | ETAGE | Group: Groupe de modèles:Pavillon type:1258082
1258056 | ETAGE | Group: Groupe de modèles:Pavillon type:1258082
1258142 | Plan des fondations Maisons 1 et 2
1258224 | Plan des fondations Maisons 1 et 2
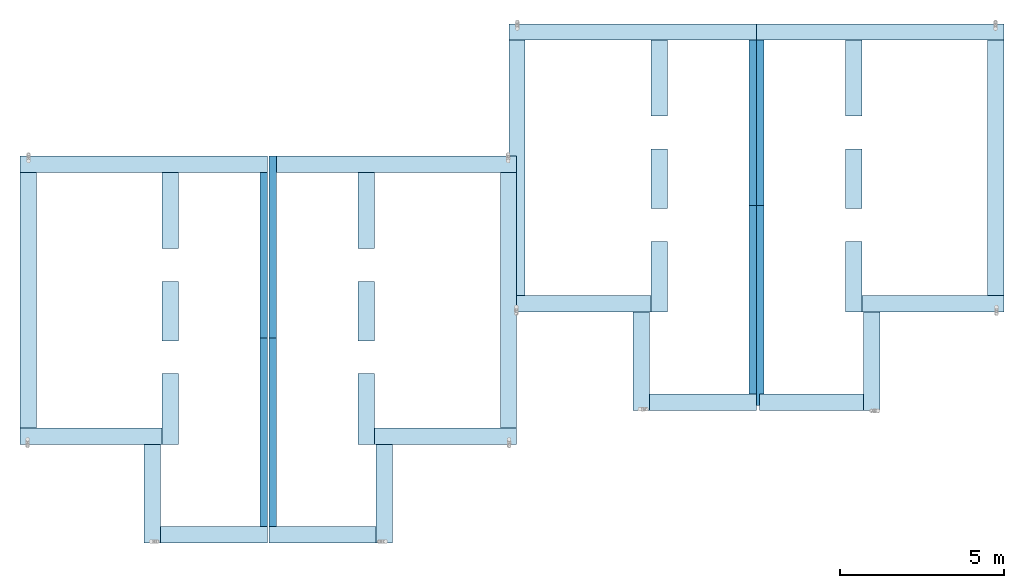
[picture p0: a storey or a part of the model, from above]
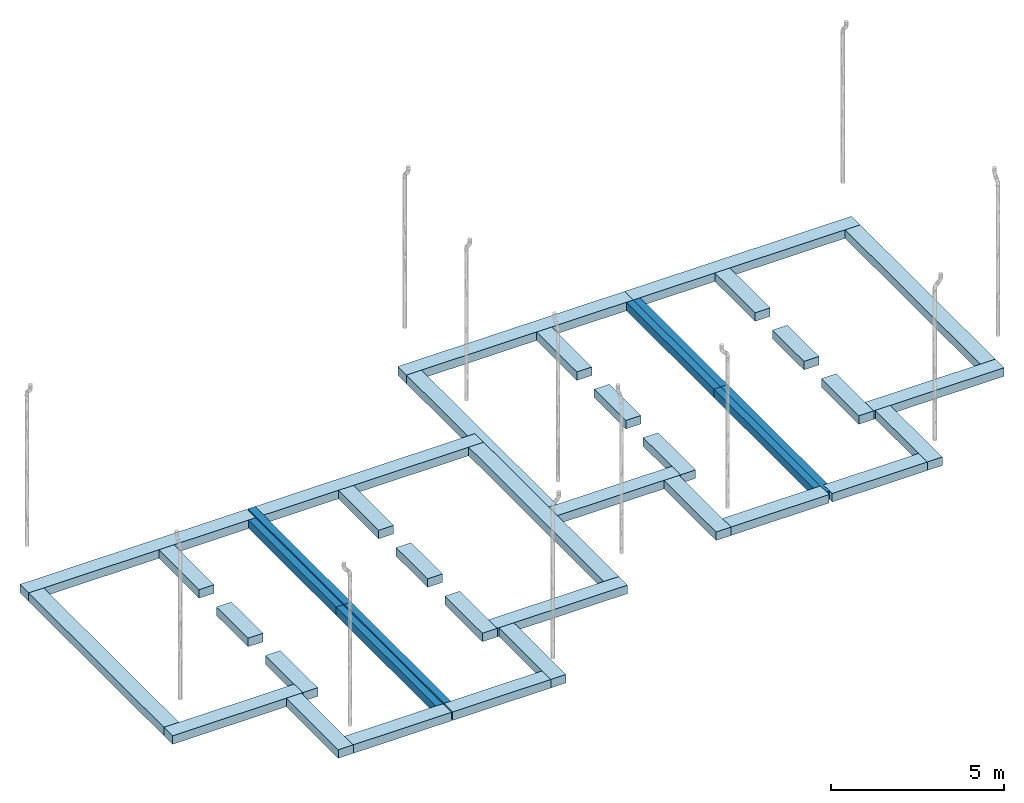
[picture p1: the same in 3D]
Properties of the parts of a building model (IFC2X3), part 2 of 2

# IfcWindow: 1.20 x 1.35 ht (19)
Name (Windows_Opening-Hinge_BOUVET_Thermience_Fenetre_2V:1.20 x 1.35 ht:...) | In
1258281 | ETAGE
1258283 | ETAGE
1283008 | Plan des fondations Maisons 1 et 2
1283089 | Plan des fondations Maisons 1 et 2
1283135 | ETAGE
1283137 | ETAGE
1360639 | Plan des fondations Maisons 1 et 2
1360713 | Plan des fondations Maisons 1 et 2
1360754 | ETAGE
1360755 | ETAGE
1360756 | ETAGE
1443885 | ETAGE

# IfcWindow: 120 x 135 cm, VR-2 Vantaux:120 x 135 cm:1258282
In: ETAGE
Type - ParameterTakesPrecedence: no; Sizeable: no; Material: PVC - Blanc, Aluminium - Satiné, Béton - Ordinaire, Verre - Opaque Blanc
OverallHeight: 1.65 m; OverallWidth: 1.3 m
Pset_QuantityTakeOff - Reference: 120 x 135 cm
Pset_WindowCommon - IsExternal: yes; Reference: 120 x 135 cm

# IfcWindow: 800 x 120 ht (4)
In: ETAGE
Type - ParameterTakesPrecedence: no; Sizeable: no; Classification: B2020100 Windows (Uniformat); Material: Plastique - Bouvet - Blanc W012, Verre - Bouvet - Vitrage, Polyamide - Bouvet - Joint-Intercalaire
OverallHeight: 1.39 m; OverallWidth: 0.88 m
Pset_ManufacturerTypeInformation - Manufacturer: BOUVET
Pset_QuantityTakeOff - Reference: 800 x 120 ht
Pset_WindowCommon - IsExternal: yes; Reference: 800 x 120 ht
Name (Windows_Opening-Hinge_BOUVET_Thermience_Fenetre_1V:800 x 120 ht:...)
1258053 | Group: Groupe de modèles:Pavillon type:1258082
1258280
1283134
1360753
